One B-rep face of a CAD part: STEP entity #132701.
In plain terms, the planar face has unit normal (0, 1, 0).
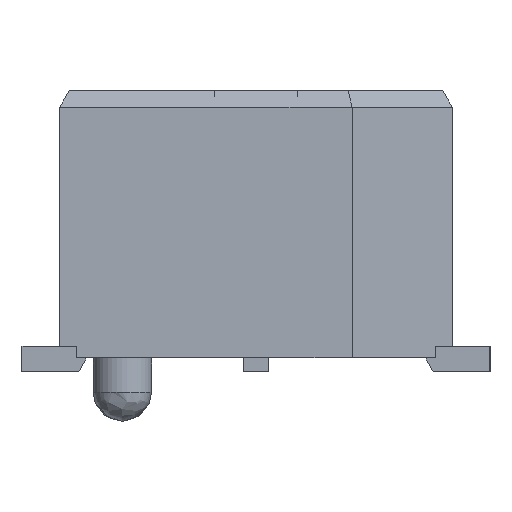
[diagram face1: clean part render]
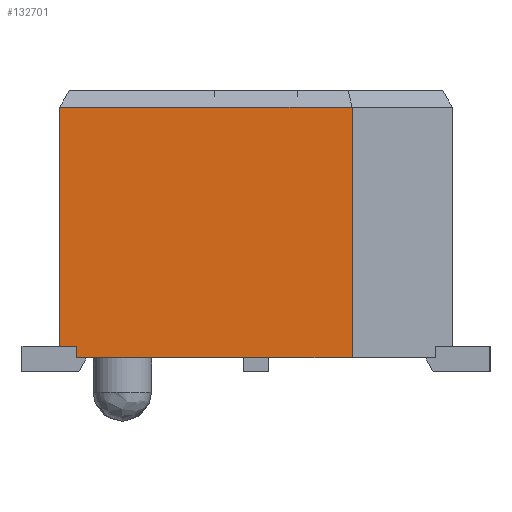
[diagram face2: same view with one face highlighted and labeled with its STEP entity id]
Its self-contained STEP definition (entity closure, numbers rounded to 3 decimals):
#131030 = PLANE('',#131031);
#131031 = AXIS2_PLACEMENT_3D('',#131032,#131033,#131034);
#131032 = CARTESIAN_POINT('',(-61.898,85.15,0.208
    ));
#131033 = DIRECTION('',(0.,0.,-1.));
#131034 = DIRECTION('',(-1.,0.,0.));
#131855 = VERTEX_POINT('',#131856);
#131856 = CARTESIAN_POINT('',(-59.167,105.152,
    0.208));
#131872 = PLANE('',#131873);
#131873 = AXIS2_PLACEMENT_3D('',#131874,#131875,#131876);
#131874 = CARTESIAN_POINT('',(-59.167,125.409,
    -1.614));
#131875 = DIRECTION('',(1.,0.,0.));
#131876 = DIRECTION('',(0.,0.,-1.));
#131969 = VERTEX_POINT('',#131970);
#131970 = CARTESIAN_POINT('',(-63.358,105.152,
    0.208));
#131984 = PLANE('',#131985);
#131985 = AXIS2_PLACEMENT_3D('',#131986,#131987,#131988);
#131986 = CARTESIAN_POINT('',(-63.358,105.152,
    4.018));
#131987 = DIRECTION('',(0.707,-0.707,
    0.));
#131988 = DIRECTION('',(0.707,0.707,0.
    ));
#131996 = EDGE_CURVE('',#131969,#131855,#131997,.T.);
#131997 = SURFACE_CURVE('',#131998,(#132002,#132009),.PCURVE_S1.);
#131998 = LINE('',#131999,#132000);
#131999 = CARTESIAN_POINT('',(-61.898,105.152,
    0.208));
#132000 = VECTOR('',#132001,1.);
#132001 = DIRECTION('',(1.,0.,0.));
#132002 = PCURVE('',#131030,#132003);
#132003 = DEFINITIONAL_REPRESENTATION('',(#132004),#132008);
#132004 = LINE('',#132005,#132006);
#132005 = CARTESIAN_POINT('',(0.,20.003));
#132006 = VECTOR('',#132007,1.);
#132007 = DIRECTION('',(-1.,0.));
#132008 = ( GEOMETRIC_REPRESENTATION_CONTEXT(2) 
PARAMETRIC_REPRESENTATION_CONTEXT() REPRESENTATION_CONTEXT('2D SPACE',''
  ) );
#132009 = PCURVE('',#132010,#132015);
#132010 = PLANE('',#132011);
#132011 = AXIS2_PLACEMENT_3D('',#132012,#132013,#132014);
#132012 = CARTESIAN_POINT('',(-58.913,105.152,
    4.018));
#132013 = DIRECTION('',(0.,-1.,0.));
#132014 = DIRECTION('',(1.,0.,0.));
#132015 = DEFINITIONAL_REPRESENTATION('',(#132016),#132020);
#132016 = LINE('',#132017,#132018);
#132017 = CARTESIAN_POINT('',(-2.985,-3.81));
#132018 = VECTOR('',#132019,1.);
#132019 = DIRECTION('',(1.,0.));
#132020 = ( GEOMETRIC_REPRESENTATION_CONTEXT(2) 
PARAMETRIC_REPRESENTATION_CONTEXT() REPRESENTATION_CONTEXT('2D SPACE',''
  ) );
#132542 = PLANE('',#132543);
#132543 = AXIS2_PLACEMENT_3D('',#132544,#132545,#132546);
#132544 = CARTESIAN_POINT('',(-59.167,125.409,
    0.386));
#132545 = DIRECTION('',(0.,0.,-1.));
#132546 = DIRECTION('',(-1.,0.,0.));
#132570 = PLANE('',#132571);
#132571 = AXIS2_PLACEMENT_3D('',#132572,#132573,#132574);
#132572 = CARTESIAN_POINT('',(-58.913,65.147,4.018
    ));
#132573 = DIRECTION('',(-1.,0.,0.));
#132574 = DIRECTION('',(0.,-1.,0.));
#132656 = EDGE_CURVE('',#131855,#132657,#132659,.T.);
#132657 = VERTEX_POINT('',#132658);
#132658 = CARTESIAN_POINT('',(-59.167,105.152,
    0.386));
#132659 = SURFACE_CURVE('',#132660,(#132664,#132671),.PCURVE_S1.);
#132660 = LINE('',#132661,#132662);
#132661 = CARTESIAN_POINT('',(-59.167,105.152,
    -1.614));
#132662 = VECTOR('',#132663,1.);
#132663 = DIRECTION('',(0.,0.,1.));
#132664 = PCURVE('',#131872,#132665);
#132665 = DEFINITIONAL_REPRESENTATION('',(#132666),#132670);
#132666 = LINE('',#132667,#132668);
#132667 = CARTESIAN_POINT('',(0.,-20.257));
#132668 = VECTOR('',#132669,1.);
#132669 = DIRECTION('',(-1.,0.));
#132670 = ( GEOMETRIC_REPRESENTATION_CONTEXT(2) 
PARAMETRIC_REPRESENTATION_CONTEXT() REPRESENTATION_CONTEXT('2D SPACE',''
  ) );
#132671 = PCURVE('',#132010,#132672);
#132672 = DEFINITIONAL_REPRESENTATION('',(#132673),#132677);
#132673 = LINE('',#132674,#132675);
#132674 = CARTESIAN_POINT('',(-0.254,-5.632));
#132675 = VECTOR('',#132676,1.);
#132676 = DIRECTION('',(0.,1.));
#132677 = ( GEOMETRIC_REPRESENTATION_CONTEXT(2) 
PARAMETRIC_REPRESENTATION_CONTEXT() REPRESENTATION_CONTEXT('2D SPACE',''
  ) );
#132701 = ADVANCED_FACE('',(#132702),#132010,.F.);
#132702 = FACE_BOUND('',#132703,.T.);
#132703 = EDGE_LOOP('',(#132704,#132705,#132728,#132756,#132779,#132800)
  );
#132704 = ORIENTED_EDGE('',*,*,#131996,.F.);
#132705 = ORIENTED_EDGE('',*,*,#132706,.F.);
#132706 = EDGE_CURVE('',#132707,#131969,#132709,.T.);
#132707 = VERTEX_POINT('',#132708);
#132708 = CARTESIAN_POINT('',(-63.358,105.152,
    4.018));
#132709 = SURFACE_CURVE('',#132710,(#132714,#132721),.PCURVE_S1.);
#132710 = LINE('',#132711,#132712);
#132711 = CARTESIAN_POINT('',(-63.358,105.152,
    4.018));
#132712 = VECTOR('',#132713,1.);
#132713 = DIRECTION('',(0.,0.,-1.));
#132714 = PCURVE('',#132010,#132715);
#132715 = DEFINITIONAL_REPRESENTATION('',(#132716),#132720);
#132716 = LINE('',#132717,#132718);
#132717 = CARTESIAN_POINT('',(-4.445,0.));
#132718 = VECTOR('',#132719,1.);
#132719 = DIRECTION('',(0.,-1.));
#132720 = ( GEOMETRIC_REPRESENTATION_CONTEXT(2) 
PARAMETRIC_REPRESENTATION_CONTEXT() REPRESENTATION_CONTEXT('2D SPACE',''
  ) );
#132721 = PCURVE('',#131984,#132722);
#132722 = DEFINITIONAL_REPRESENTATION('',(#132723),#132727);
#132723 = LINE('',#132724,#132725);
#132724 = CARTESIAN_POINT('',(0.,0.));
#132725 = VECTOR('',#132726,1.);
#132726 = DIRECTION('',(0.,-1.));
#132727 = ( GEOMETRIC_REPRESENTATION_CONTEXT(2) 
PARAMETRIC_REPRESENTATION_CONTEXT() REPRESENTATION_CONTEXT('2D SPACE',''
  ) );
#132728 = ORIENTED_EDGE('',*,*,#132729,.F.);
#132729 = EDGE_CURVE('',#132730,#132707,#132732,.T.);
#132730 = VERTEX_POINT('',#132731);
#132731 = CARTESIAN_POINT('',(-58.913,105.152,
    4.018));
#132732 = SURFACE_CURVE('',#132733,(#132737,#132744),.PCURVE_S1.);
#132733 = LINE('',#132734,#132735);
#132734 = CARTESIAN_POINT('',(-58.913,105.152,
    4.018));
#132735 = VECTOR('',#132736,1.);
#132736 = DIRECTION('',(-1.,0.,0.));
#132737 = PCURVE('',#132010,#132738);
#132738 = DEFINITIONAL_REPRESENTATION('',(#132739),#132743);
#132739 = LINE('',#132740,#132741);
#132740 = CARTESIAN_POINT('',(0.,0.));
#132741 = VECTOR('',#132742,1.);
#132742 = DIRECTION('',(-1.,0.));
#132743 = ( GEOMETRIC_REPRESENTATION_CONTEXT(2) 
PARAMETRIC_REPRESENTATION_CONTEXT() REPRESENTATION_CONTEXT('2D SPACE',''
  ) );
#132744 = PCURVE('',#132745,#132750);
#132745 = PLANE('',#132746);
#132746 = AXIS2_PLACEMENT_3D('',#132747,#132748,#132749);
#132747 = CARTESIAN_POINT('',(-58.913,105.152,
    4.018));
#132748 = DIRECTION('',(0.,0.866,0.5));
#132749 = DIRECTION('',(0.,-0.5,0.866));
#132750 = DEFINITIONAL_REPRESENTATION('',(#132751),#132755);
#132751 = LINE('',#132752,#132753);
#132752 = CARTESIAN_POINT('',(0.,0.));
#132753 = VECTOR('',#132754,1.);
#132754 = DIRECTION('',(0.,-1.));
#132755 = ( GEOMETRIC_REPRESENTATION_CONTEXT(2) 
PARAMETRIC_REPRESENTATION_CONTEXT() REPRESENTATION_CONTEXT('2D SPACE',''
  ) );
#132756 = ORIENTED_EDGE('',*,*,#132757,.F.);
#132757 = EDGE_CURVE('',#132758,#132730,#132760,.T.);
#132758 = VERTEX_POINT('',#132759);
#132759 = CARTESIAN_POINT('',(-58.913,105.152,
    0.386));
#132760 = SURFACE_CURVE('',#132761,(#132765,#132772),.PCURVE_S1.);
#132761 = LINE('',#132762,#132763);
#132762 = CARTESIAN_POINT('',(-58.913,105.152,
    4.018));
#132763 = VECTOR('',#132764,1.);
#132764 = DIRECTION('',(0.,0.,1.));
#132765 = PCURVE('',#132010,#132766);
#132766 = DEFINITIONAL_REPRESENTATION('',(#132767),#132771);
#132767 = LINE('',#132768,#132769);
#132768 = CARTESIAN_POINT('',(0.,0.));
#132769 = VECTOR('',#132770,1.);
#132770 = DIRECTION('',(0.,1.));
#132771 = ( GEOMETRIC_REPRESENTATION_CONTEXT(2) 
PARAMETRIC_REPRESENTATION_CONTEXT() REPRESENTATION_CONTEXT('2D SPACE',''
  ) );
#132772 = PCURVE('',#132570,#132773);
#132773 = DEFINITIONAL_REPRESENTATION('',(#132774),#132778);
#132774 = LINE('',#132775,#132776);
#132775 = CARTESIAN_POINT('',(-40.005,0.));
#132776 = VECTOR('',#132777,1.);
#132777 = DIRECTION('',(0.,1.));
#132778 = ( GEOMETRIC_REPRESENTATION_CONTEXT(2) 
PARAMETRIC_REPRESENTATION_CONTEXT() REPRESENTATION_CONTEXT('2D SPACE',''
  ) );
#132779 = ORIENTED_EDGE('',*,*,#132780,.F.);
#132780 = EDGE_CURVE('',#132657,#132758,#132781,.T.);
#132781 = SURFACE_CURVE('',#132782,(#132786,#132793),.PCURVE_S1.);
#132782 = LINE('',#132783,#132784);
#132783 = CARTESIAN_POINT('',(-58.913,105.152,
    0.386));
#132784 = VECTOR('',#132785,1.);
#132785 = DIRECTION('',(1.,0.,0.));
#132786 = PCURVE('',#132010,#132787);
#132787 = DEFINITIONAL_REPRESENTATION('',(#132788),#132792);
#132788 = LINE('',#132789,#132790);
#132789 = CARTESIAN_POINT('',(0.,-3.632));
#132790 = VECTOR('',#132791,1.);
#132791 = DIRECTION('',(1.,0.));
#132792 = ( GEOMETRIC_REPRESENTATION_CONTEXT(2) 
PARAMETRIC_REPRESENTATION_CONTEXT() REPRESENTATION_CONTEXT('2D SPACE',''
  ) );
#132793 = PCURVE('',#132542,#132794);
#132794 = DEFINITIONAL_REPRESENTATION('',(#132795),#132799);
#132795 = LINE('',#132796,#132797);
#132796 = CARTESIAN_POINT('',(-0.254,-20.257));
#132797 = VECTOR('',#132798,1.);
#132798 = DIRECTION('',(-1.,0.));
#132799 = ( GEOMETRIC_REPRESENTATION_CONTEXT(2) 
PARAMETRIC_REPRESENTATION_CONTEXT() REPRESENTATION_CONTEXT('2D SPACE',''
  ) );
#132800 = ORIENTED_EDGE('',*,*,#132656,.F.);
